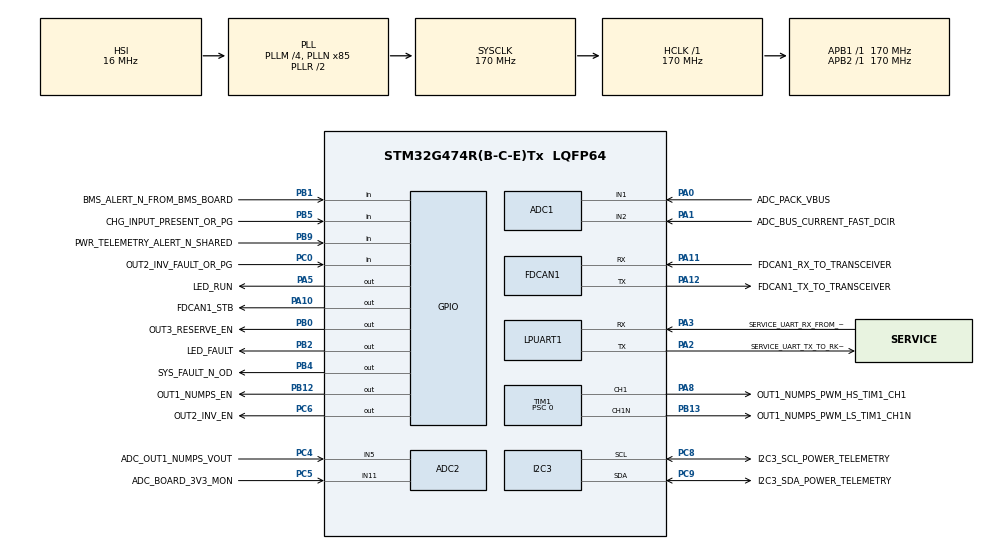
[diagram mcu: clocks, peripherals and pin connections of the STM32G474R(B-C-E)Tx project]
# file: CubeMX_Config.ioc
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ADC1.Channel-0\#ChannelRegularConversion=ADC_CHANNEL_1
ADC1.Channel-1\#ChannelRegularConversion=ADC_CHANNEL_2
ADC1.NbrOfConversionFlag=2
ADC1.OffsetNumber-0\#ChannelRegularConversion=ADC_OFFSET_NONE
ADC1.OffsetNumber-1\#ChannelRegularConversion=ADC_OFFSET_NONE
ADC1.Rank-0\#ChannelRegularConversion=1
ADC1.Rank-1\#ChannelRegularConversion=2
ADC1.SamplingTime-0\#ChannelRegularConversion=ADC_SAMPLETIME_47CYCLES_5
ADC1.SamplingTime-1\#ChannelRegularConversion=ADC_SAMPLETIME_47CYCLES_5
ADC1.master=1
ADC2.Channel-0\#ChannelRegularConversion=ADC_CHANNEL_5
ADC2.Channel-1\#ChannelRegularConversion=ADC_CHANNEL_11
ADC2.NbrOfConversionFlag=2
ADC2.OffsetNumber-0\#ChannelRegularConversion=ADC_OFFSET_NONE
ADC2.OffsetNumber-1\#ChannelRegularConversion=ADC_OFFSET_NONE
ADC2.Rank-0\#ChannelRegularConversion=1
ADC2.Rank-1\#ChannelRegularConversion=2
ADC2.SamplingTime-0\#ChannelRegularConversion=ADC_SAMPLETIME_47CYCLES_5
ADC2.SamplingTime-1\#ChannelRegularConversion=ADC_SAMPLETIME_47CYCLES_5
FDCAN1.AutoRetransmission=ENABLE
FDCAN1.CalculateBaudRateNominal=500000
FDCAN1.CalculateTimeBitNominal=2000
FDCAN1.CalculateTimeQuantumNominal=100.0
FDCAN1.ExtFiltersNbr=1
FDCAN1.FrameFormat=FDCAN_FRAME_CLASSIC
FDCAN1.Mode=FDCAN_MODE_NORMAL
FDCAN1.NominalPrescaler=17
FDCAN1.NominalSyncJumpWidth=3
FDCAN1.NominalTimeSeg1=16
FDCAN1.NominalTimeSeg2=3
FDCAN1.StdFiltersNbr=1
I2C3.Timing=0x40B285C2
Mcu.Family=STM32G4
Mcu.Name=STM32G474R(B-C-E)Tx
Mcu.Package=LQFP64
NVIC.PriorityGroup=NVIC_PRIORITYGROUP_4
PA0.GPIO_Label=ADC_PACK_VBUS
PA0.Mode=IN1-Single-Ended
PA0.Signal=ADC1_IN1
PA1.GPIO_Label=ADC_BUS_CURRENT_FAST_DCIR
PA1.Mode=IN2-Single-Ended
PA1.Signal=ADC1_IN2
PA10.GPIO_Label=FDCAN1_STB
PA10.GPIO_ModeDefaultOutputPP=GPIO_MODE_OUTPUT_PP
PA10.GPIO_PuPd=GPIO_PULLDOWN
PA10.PinState=GPIO_PIN_RESET
PA10.Signal=GPIO_Output
PA11.GPIO_Label=FDCAN1_RX_TO_TRANSCEIVER
PA11.Mode=FDCAN_Activate
PA11.Signal=FDCAN1_RX
PA12.GPIO_Label=FDCAN1_TX_TO_TRANSCEIVER
PA12.Mode=FDCAN_Activate
PA12.Signal=FDCAN1_TX
PA13.Mode=Serial_Wire
PA13.Signal=SYS_JTMS-SWDIO
PA14.Mode=Serial_Wire
PA14.Signal=SYS_JTCK-SWCLK
PA2.Mode=Asynchronous
PA2.GPIO_Label=SERVICE_UART_TX_TO_RK3506_OR_USBTTL
PA2.Signal=LPUART1_TX
PA3.Mode=Asynchronous
PA3.GPIO_Label=SERVICE_UART_RX_FROM_RK3506_OR_USBTTL
PA3.Signal=LPUART1_RX
PA5.GPIO_Label=LED_RUN
PA5.GPIO_ModeDefaultOutputPP=GPIO_MODE_OUTPUT_PP
PA5.PinState=GPIO_PIN_RESET
PA5.Signal=GPIO_Output
PA8.GPIO_Label=OUT1_NUMPS_PWM_HS_TIM1_CH1
PA8.Signal=S_TIM1_CH1
PB4.GPIO_Label=SYS_FAULT_N_OD
PB4.GPIO_ModeDefaultOutputPP=GPIO_MODE_OUTPUT_OD
PB4.GPIO_PuPd=GPIO_NOPULL
PB4.PinState=GPIO_PIN_SET
PB4.Signal=GPIO_Output
PB0.GPIO_Label=OUT3_RESERVE_EN
PB0.GPIO_ModeDefaultOutputPP=GPIO_MODE_OUTPUT_PP
PB0.PinState=GPIO_PIN_RESET
PB0.Signal=GPIO_Output
PB1.GPIO_Label=BMS_ALERT_N_FROM_BMS_BOARD
PB1.GPIO_PuPd=GPIO_PULLUP
PB1.Signal=GPIO_Input
PB12.GPIO_Label=OUT1_NUMPS_EN
PB12.GPIO_ModeDefaultOutputPP=GPIO_MODE_OUTPUT_PP
PB12.GPIO_PuPd=GPIO_PULLDOWN
PB12.PinState=GPIO_PIN_RESET
PB12.Signal=GPIO_Output
PB13.GPIO_Label=OUT1_NUMPS_PWM_LS_TIM1_CH1N
PB13.Mode=PWM Generation1 CH1N
PB13.Signal=TIM1_CH1N
PB2.GPIO_Label=LED_FAULT
PB2.GPIO_ModeDefaultOutputPP=GPIO_MODE_OUTPUT_PP
PB2.PinState=GPIO_PIN_RESET
PB2.Signal=GPIO_Output
PB5.GPIO_Label=CHG_INPUT_PRESENT_OR_PG
PB5.GPIO_PuPd=GPIO_PULLDOWN
PB5.Signal=GPIO_Input
PB9.GPIO_Label=PWR_TELEMETRY_ALERT_N_SHARED
PB9.GPIO_PuPd=GPIO_PULLUP
PB9.Signal=GPIO_Input
PC0.GPIO_Label=OUT2_INV_FAULT_OR_PG
PC0.GPIO_PuPd=GPIO_PULLUP
PC0.Signal=GPIO_Input
PC14-OSC32_IN.Mode=LSE-External-Oscillator
PC14-OSC32_IN.Signal=RCC_OSC32_IN
PC15-OSC32_OUT.Mode=LSE-External-Oscillator
PC15-OSC32_OUT.Signal=RCC_OSC32_OUT
PC4.GPIO_Label=ADC_OUT1_NUMPS_VOUT
PC4.Mode=IN5-Single-Ended
PC4.Signal=ADC2_IN5
PC5.GPIO_Label=ADC_BOARD_3V3_MON
PC5.Mode=IN11-Single-Ended
PC5.Signal=ADC2_IN11
PC6.GPIO_Label=OUT2_INV_EN
PC6.GPIO_ModeDefaultOutputPP=GPIO_MODE_OUTPUT_PP
PC6.GPIO_PuPd=GPIO_PULLDOWN
PC6.PinState=GPIO_PIN_RESET
PC6.Signal=GPIO_Output
PC8.Mode=I2C
PC8.GPIO_Label=I2C3_SCL_POWER_TELEMETRY
PC8.Signal=I2C3_SCL
PC9.Mode=I2C
PC9.GPIO_Label=I2C3_SDA_POWER_TELEMETRY
PC9.Signal=I2C3_SDA
PF0-OSC_IN.Mode=HSE-External-Oscillator
PF0-OSC_IN.Signal=RCC_OSC_IN
PF1-OSC_OUT.Mode=HSE-External-Oscillator
PF1-OSC_OUT.Signal=RCC_OSC_OUT
ProjectManager.HeapSize=0x200
ProjectManager.StackSize=0x400
ProjectManager.TargetToolchain=MDK-ARM V5
RCC.ADC12Freq_Value=170000000
RCC.ADC345Freq_Value=170000000
RCC.AHBFreq_Value=170000000
RCC.APB1Freq_Value=170000000
RCC.APB1TimFreq_Value=170000000
RCC.APB2Freq_Value=170000000
RCC.APB2TimFreq_Value=170000000
RCC.CortexFreq_Value=170000000
RCC.EXTERNAL_CLOCK_VALUE=12288000
RCC.HCLKFreq_Value=170000000
RCC.HSE_VALUE=24000000
RCC.HSI48_VALUE=48000000
RCC.HSI_VALUE=16000000
RCC.PLLM=RCC_PLLM_DIV4
RCC.PLLN=85
RCC.RTCClockSelection=RCC_RTCCLKSOURCE_LSE
RCC.SYSCLKFreq_VALUE=170000000
RCC.SYSCLKSource=RCC_SYSCLKSOURCE_PLLCLK
RCC.USBFreq_Value=170000000
RCC.VCOOutputFreq_Value=340000000
SH.S_TIM1_CH1.0=TIM1_CH1,PWM Generation1 CH1
TIM1.Channel-PWM\ Generation1\ CH1=TIM_CHANNEL_1
TIM1.Channel-PWM\ Generation1\ CH1N=TIM_CHANNEL_1
TIM1.Period=4358
TIM1.Prescaler=0
TIM1.Pulse-PWM\ Generation1\ CH1=0
VP_SYS_VS_DBSignals.Mode=DisableDeadBatterySignals
VP_TIM1_VS_ClockSourceINT.Mode=Internal
board=NUCLEO-G474RE

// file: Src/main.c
/* USER CODE BEGIN Header */
/**
  ******************************************************************************
  * @file           : main.c
  * @brief          : Main program body
  ******************************************************************************
  * @attention
  *
  * Copyright (c) 2026 STMicroelectronics.
  * All rights reserved.
  *
  * This software is licensed under terms that can be found in the LICENSE file
  * in the root directory of this software component.
  * If no LICENSE file comes with this software, it is provided AS-IS.
  *
  ******************************************************************************
  */
/* USER CODE END Header */
#include "main.h"

ADC_HandleTypeDef hadc1;
ADC_HandleTypeDef hadc2;

FDCAN_HandleTypeDef hfdcan1;

I2C_HandleTypeDef hi2c3;

UART_HandleTypeDef hlpuart1;

TIM_HandleTypeDef htim1;

void SystemClock_Config(void);
static void MX_GPIO_Init(void);
static void MX_ADC1_Init(void);
static void MX_ADC2_Init(void);
static void MX_TIM1_Init(void);
static void MX_FDCAN1_Init(void);
static void MX_I2C3_Init(void);
static void MX_LPUART1_UART_Init(void);

int main(void)
{

  /* MCU Configuration--------------------------------------------------------*/

  /* Reset of all peripherals, Initializes the Flash interface and the Systick. */
  HAL_Init();

  /* Configure the system clock */
  SystemClock_Config();

  /* Initialize all configured peripherals */
  MX_GPIO_Init();
  MX_ADC1_Init();
  MX_ADC2_Init();
  MX_TIM1_Init();
  MX_FDCAN1_Init();
  MX_I2C3_Init();
  MX_LPUART1_UART_Init();

  /* Infinite loop */
  while (1)
  {

  }
}

void SystemClock_Config(void)
{
  RCC_OscInitTypeDef RCC_OscInitStruct = {0};
  RCC_ClkInitTypeDef RCC_ClkInitStruct = {0};

  /** Configure the main internal regulator output voltage
  */
  HAL_PWREx_ControlVoltageScaling(PWR_REGULATOR_VOLTAGE_SCALE1_BOOST);

  /** Initializes the RCC Oscillators according to the specified parameters
  * in the RCC_OscInitTypeDef structure.
  */
  RCC_OscInitStruct.OscillatorType = RCC_OSCILLATORTYPE_HSI;
  RCC_OscInitStruct.HSIState = RCC_HSI_ON;
  RCC_OscInitStruct.HSICalibrationValue = RCC_HSICALIBRATION_DEFAULT;
  RCC_OscInitStruct.PLL.PLLState = RCC_PLL_ON;
  RCC_OscInitStruct.PLL.PLLSource = RCC_PLLSOURCE_HSI;
  RCC_OscInitStruct.PLL.PLLM = RCC_PLLM_DIV4;
  RCC_OscInitStruct.PLL.PLLN = 85;
  RCC_OscInitStruct.PLL.PLLP = RCC_PLLP_DIV2;
  RCC_OscInitStruct.PLL.PLLQ = RCC_PLLQ_DIV2;
  RCC_OscInitStruct.PLL.PLLR = RCC_PLLR_DIV2;
  if (HAL_RCC_OscConfig(&RCC_OscInitStruct) != HAL_OK)
  {
    Error_Handler();
  }

  /** Initializes the CPU, AHB and APB buses clocks
  */
  RCC_ClkInitStruct.ClockType = RCC_CLOCKTYPE_HCLK|RCC_CLOCKTYPE_SYSCLK
                              |RCC_CLOCKTYPE_PCLK1|RCC_CLOCKTYPE_PCLK2;
  RCC_ClkInitStruct.SYSCLKSource = RCC_SYSCLKSOURCE_PLLCLK;
  RCC_ClkInitStruct.AHBCLKDivider = RCC_SYSCLK_DIV1;
  RCC_ClkInitStruct.APB1CLKDivider = RCC_HCLK_DIV1;
  RCC_ClkInitStruct.APB2CLKDivider = RCC_HCLK_DIV1;

  if (HAL_RCC_ClockConfig(&RCC_ClkInitStruct, FLASH_LATENCY_4) != HAL_OK)
  {
    Error_Handler();
  }
}

static void MX_ADC1_Init(void)
{

  ADC_MultiModeTypeDef multimode = {0};
  ADC_ChannelConfTypeDef sConfig = {0};

  /** Common config
  */
  hadc1.Instance = ADC1;
  hadc1.Init.ClockPrescaler = ADC_CLOCK_SYNC_PCLK_DIV4;
  hadc1.Init.Resolution = ADC_RESOLUTION_12B;
  hadc1.Init.DataAlign = ADC_DATAALIGN_RIGHT;
  hadc1.Init.GainCompensation = 0;
  hadc1.Init.ScanConvMode = ADC_SCAN_DISABLE;
  hadc1.Init.EOCSelection = ADC_EOC_SINGLE_CONV;
  hadc1.Init.LowPowerAutoWait = DISABLE;
  hadc1.Init.ContinuousConvMode = DISABLE;
  hadc1.Init.NbrOfConversion = 1;
  hadc1.Init.DiscontinuousConvMode = DISABLE;
  hadc1.Init.ExternalTrigConv = ADC_SOFTWARE_START;
  hadc1.Init.ExternalTrigConvEdge = ADC_EXTERNALTRIGCONVEDGE_NONE;
  hadc1.Init.DMAContinuousRequests = DISABLE;
  hadc1.Init.Overrun = ADC_OVR_DATA_PRESERVED;
  hadc1.Init.OversamplingMode = DISABLE;
  if (HAL_ADC_Init(&hadc1) != HAL_OK)
  {
    Error_Handler();
  }

  /** Configure the ADC multi-mode
  */
  multimode.Mode = ADC_MODE_INDEPENDENT;
  if (HAL_ADCEx_MultiModeConfigChannel(&hadc1, &multimode) != HAL_OK)
  {
    Error_Handler();
  }

  /** Configure Regular Channel
  */
  sConfig.Channel = ADC_CHANNEL_1;
  sConfig.Rank = ADC_REGULAR_RANK_1;
  sConfig.SamplingTime = ADC_SAMPLETIME_2CYCLES_5;
  sConfig.SingleDiff = ADC_SINGLE_ENDED;
  sConfig.OffsetNumber = ADC_OFFSET_NONE;
  sConfig.Offset = 0;
  if (HAL_ADC_ConfigChannel(&hadc1, &sConfig) != HAL_OK)
  {
    Error_Handler();
  }

}

static void MX_ADC2_Init(void)
{

  ADC_ChannelConfTypeDef sConfig = {0};

  /** Common config
  */
  hadc2.Instance = ADC2;
  hadc2.Init.ClockPrescaler = ADC_CLOCK_SYNC_PCLK_DIV4;
  hadc2.Init.Resolution = ADC_RESOLUTION_12B;
  hadc2.Init.DataAlign = ADC_DATAALIGN_RIGHT;
  hadc2.Init.GainCompensation = 0;
  hadc2.Init.ScanConvMode = ADC_SCAN_DISABLE;
  hadc2.Init.EOCSelection = ADC_EOC_SINGLE_CONV;
  hadc2.Init.LowPowerAutoWait = DISABLE;
  hadc2.Init.ContinuousConvMode = DISABLE;
  hadc2.Init.NbrOfConversion = 1;
  hadc2.Init.DiscontinuousConvMode = DISABLE;
  hadc2.Init.ExternalTrigConv = ADC_SOFTWARE_START;
  hadc2.Init.ExternalTrigConvEdge = ADC_EXTERNALTRIGCONVEDGE_NONE;
  hadc2.Init.DMAContinuousRequests = DISABLE;
  hadc2.Init.Overrun = ADC_OVR_DATA_PRESERVED;
  hadc2.Init.OversamplingMode = DISABLE;
  if (HAL_ADC_Init(&hadc2) != HAL_OK)
  {
    Error_Handler();
  }

  /** Configure Regular Channel
  */
  sConfig.Channel = ADC_CHANNEL_5;
  sConfig.Rank = ADC_REGULAR_RANK_1;
  sConfig.SamplingTime = ADC_SAMPLETIME_2CYCLES_5;
  sConfig.SingleDiff = ADC_SINGLE_ENDED;
  sConfig.OffsetNumber = ADC_OFFSET_NONE;
  sConfig.Offset = 0;
  if (HAL_ADC_ConfigChannel(&hadc2, &sConfig) != HAL_OK)
  {
    Error_Handler();
  }

}

static void MX_FDCAN1_Init(void)
{

  hfdcan1.Instance = FDCAN1;
  hfdcan1.Init.ClockDivider = FDCAN_CLOCK_DIV1;
  hfdcan1.Init.FrameFormat = FDCAN_FRAME_CLASSIC;
  hfdcan1.Init.Mode = FDCAN_MODE_NORMAL;
  hfdcan1.Init.AutoRetransmission = ENABLE;
  hfdcan1.Init.TransmitPause = DISABLE;
  hfdcan1.Init.ProtocolException = DISABLE;
  hfdcan1.Init.NominalPrescaler = 17;
  hfdcan1.Init.NominalSyncJumpWidth = 3;
  hfdcan1.Init.NominalTimeSeg1 = 16;
  hfdcan1.Init.NominalTimeSeg2 = 3;
  hfdcan1.Init.DataPrescaler = 1;
  hfdcan1.Init.DataSyncJumpWidth = 1;
  hfdcan1.Init.DataTimeSeg1 = 1;
  hfdcan1.Init.DataTimeSeg2 = 1;
  hfdcan1.Init.StdFiltersNbr = 1;
  hfdcan1.Init.ExtFiltersNbr = 1;
  hfdcan1.Init.TxFifoQueueMode = FDCAN_TX_FIFO_OPERATION;
  if (HAL_FDCAN_Init(&hfdcan1) != HAL_OK)
  {
    Error_Handler();
  }

}

static void MX_I2C3_Init(void)
{

  hi2c3.Instance = I2C3;
  hi2c3.Init.Timing = 0x40B285C2;
  hi2c3.Init.OwnAddress1 = 0;
  hi2c3.Init.AddressingMode = I2C_ADDRESSINGMODE_7BIT;
  hi2c3.Init.DualAddressMode = I2C_DUALADDRESS_DISABLE;
  hi2c3.Init.OwnAddress2 = 0;
  hi2c3.Init.OwnAddress2Masks = I2C_OA2_NOMASK;
  hi2c3.Init.GeneralCallMode = I2C_GENERALCALL_DISABLE;
  hi2c3.Init.NoStretchMode = I2C_NOSTRETCH_DISABLE;
  if (HAL_I2C_Init(&hi2c3) != HAL_OK)
  {
    Error_Handler();
  }

  /** Configure Analogue filter
  */
  if (HAL_I2CEx_ConfigAnalogFilter(&hi2c3, I2C_ANALOGFILTER_ENABLE) != HAL_OK)
  {
    Error_Handler();
  }

  /** Configure Digital filter
  */
  if (HAL_I2CEx_ConfigDigitalFilter(&hi2c3, 0) != HAL_OK)
  {
    Error_Handler();
  }

}

static void MX_LPUART1_UART_Init(void)
{

  hlpuart1.Instance = LPUART1;
  hlpuart1.Init.BaudRate = 209700;
  hlpuart1.Init.WordLength = UART_WORDLENGTH_8B;
  hlpuart1.Init.StopBits = UART_STOPBITS_1;
  hlpuart1.Init.Parity = UART_PARITY_NONE;
  hlpuart1.Init.Mode = UART_MODE_TX_RX;
  hlpuart1.Init.HwFlowCtl = UART_HWCONTROL_NONE;
  hlpuart1.Init.OneBitSampling = UART_ONE_BIT_SAMPLE_DISABLE;
  hlpuart1.Init.ClockPrescaler = UART_PRESCALER_DIV1;
  hlpuart1.AdvancedInit.AdvFeatureInit = UART_ADVFEATURE_NO_INIT;
  if (HAL_UART_Init(&hlpuart1) != HAL_OK)
  {
    Error_Handler();
  }
  if (HAL_UARTEx_SetTxFifoThreshold(&hlpuart1, UART_TXFIFO_THRESHOLD_1_8) != HAL_OK)
  {
    Error_Handler();
  }
  if (HAL_UARTEx_SetRxFifoThreshold(&hlpuart1, UART_RXFIFO_THRESHOLD_1_8) != HAL_OK)
  {
    Error_Handler();
  }
  if (HAL_UARTEx_DisableFifoMode(&hlpuart1) != HAL_OK)
  {
    Error_Handler();
  }

}

static void MX_TIM1_Init(void)
{

  TIM_ClockConfigTypeDef sClockSourceConfig = {0};
  TIM_MasterConfigTypeDef sMasterConfig = {0};
  TIM_OC_InitTypeDef sConfigOC = {0};
  TIM_BreakDeadTimeConfigTypeDef sBreakDeadTimeConfig = {0};

  htim1.Instance = TIM1;
  htim1.Init.Prescaler = 0;
  htim1.Init.CounterMode = TIM_COUNTERMODE_UP;
  htim1.Init.Period = 4358;
  htim1.Init.ClockDivision = TIM_CLOCKDIVISION_DIV1;
  htim1.Init.RepetitionCounter = 0;
  htim1.Init.AutoReloadPreload = TIM_AUTORELOAD_PRELOAD_DISABLE;
  if (HAL_TIM_Base_Init(&htim1) != HAL_OK)
  {
    Error_Handler();
  }
  sClockSourceConfig.ClockSource = TIM_CLOCKSOURCE_INTERNAL;
  if (HAL_TIM_ConfigClockSource(&htim1, &sClockSourceConfig) != HAL_OK)
  {
    Error_Handler();
  }
  if (HAL_TIM_PWM_Init(&htim1) != HAL_OK)
  {
    Error_Handler();
  }
  sMasterConfig.MasterOutputTrigger = TIM_TRGO_RESET;
  sMasterConfig.MasterOutputTrigger2 = TIM_TRGO2_RESET;
  sMasterConfig.MasterSlaveMode = TIM_MASTERSLAVEMODE_DISABLE;
  if (HAL_TIMEx_MasterConfigSynchronization(&htim1, &sMasterConfig) != HAL_OK)
  {
    Error_Handler();
  }
  sConfigOC.OCMode = TIM_OCMODE_PWM1;
  sConfigOC.Pulse = 0;
  sConfigOC.OCPolarity = TIM_OCPOLARITY_HIGH;
  sConfigOC.OCNPolarity = TIM_OCNPOLARITY_HIGH;
  sConfigOC.OCFastMode = TIM_OCFAST_DISABLE;
  sConfigOC.OCIdleState = TIM_OCIDLESTATE_RESET;
  sConfigOC.OCNIdleState = TIM_OCNIDLESTATE_RESET;
  if (HAL_TIM_PWM_ConfigChannel(&htim1, &sConfigOC, TIM_CHANNEL_1) != HAL_OK)
  {
    Error_Handler();
  }
  sBreakDeadTimeConfig.OffStateRunMode = TIM_OSSR_DISABLE;
  sBreakDeadTimeConfig.OffStateIDLEMode = TIM_OSSI_DISABLE;
  sBreakDeadTimeConfig.LockLevel = TIM_LOCKLEVEL_OFF;
  sBreakDeadTimeConfig.DeadTime = 0;
  sBreakDeadTimeConfig.BreakState = TIM_BREAK_DISABLE;
  sBreakDeadTimeConfig.BreakPolarity = TIM_BREAKPOLARITY_HIGH;
  sBreakDeadTimeConfig.BreakFilter = 0;
  sBreakDeadTimeConfig.BreakAFMode = TIM_BREAK_AFMODE_INPUT;
  sBreakDeadTimeConfig.Break2State = TIM_BREAK2_DISABLE;
  sBreakDeadTimeConfig.Break2Polarity = TIM_BREAK2POLARITY_HIGH;
  sBreakDeadTimeConfig.Break2Filter = 0;
  sBreakDeadTimeConfig.Break2AFMode = TIM_BREAK_AFMODE_INPUT;
  sBreakDeadTimeConfig.AutomaticOutput = TIM_AUTOMATICOUTPUT_DISABLE;
  if (HAL_TIMEx_ConfigBreakDeadTime(&htim1, &sBreakDeadTimeConfig) != HAL_OK)
  {
    Error_Handler();
  }
  HAL_TIM_MspPostInit(&htim1);

}

static void MX_GPIO_Init(void)
{
  GPIO_InitTypeDef GPIO_InitStruct = {0};

  /* GPIO Ports Clock Enable */
  __HAL_RCC_GPIOC_CLK_ENABLE();
  __HAL_RCC_GPIOF_CLK_ENABLE();
  __HAL_RCC_GPIOA_CLK_ENABLE();
  __HAL_RCC_GPIOB_CLK_ENABLE();

  /*Configure GPIO pin Output Level */
  HAL_GPIO_WritePin(NUCLEO_LD2_TEST_NEW_GPIO_Port, NUCLEO_LD2_TEST_NEW_Pin, GPIO_PIN_RESET);

  /*Configure GPIO pin Output Level */
  HAL_GPIO_WritePin(FAULT_N_OD_NEW_FROM_PCB03_HARDWIRE_GPIO_Port, FAULT_N_OD_NEW_FROM_PCB03_HARDWIRE_Pin, GPIO_PIN_SET);

  /*Configure GPIO pin Output Level */
  HAL_GPIO_WritePin(GPIOB, FAN_EN_FROM_ESP32_GPIO16_FAN_Pin|LED_RUN_FROM_ESP32_GPIO2_LED_Pin|LED_FAULT_NEW_Pin|DRV_EN_FROM_ESP32_GPIO32_BUCK_EN_Pin, GPIO_PIN_RESET);

  /*Configure GPIO pin Output Level */
  HAL_GPIO_WritePin(BACKFLOW_EN_FROM_ESP32_GPIO27_BACKFLOW_MOSFET_GPIO_Port, BACKFLOW_EN_FROM_ESP32_GPIO27_BACKFLOW_MOSFET_Pin, GPIO_PIN_RESET);

  /*Configure GPIO pin Output Level */
  HAL_GPIO_WritePin(CAN_STB_GPIO_Port, CAN_STB_Pin, GPIO_PIN_RESET);

  /*Configure GPIO pin : INA226_PV_ALERT_FROM_ESP32_GPIO35_Pin */
  GPIO_InitStruct.Pin = INA226_PV_ALERT_FROM_ESP32_GPIO35_Pin;
  GPIO_InitStruct.Mode = GPIO_MODE_INPUT;
  GPIO_InitStruct.Pull = GPIO_PULLUP;
  HAL_GPIO_Init(INA226_PV_ALERT_FROM_ESP32_GPIO35_GPIO_Port, &GPIO_InitStruct);

  /*Configure GPIO pin : NUCLEO_LD2_TEST_NEW_Pin */
  GPIO_InitStruct.Pin = NUCLEO_LD2_TEST_NEW_Pin;
  GPIO_InitStruct.Mode = GPIO_MODE_OUTPUT_PP;
  GPIO_InitStruct.Pull = GPIO_NOPULL;
  GPIO_InitStruct.Speed = GPIO_SPEED_FREQ_LOW;
  HAL_GPIO_Init(NUCLEO_LD2_TEST_NEW_GPIO_Port, &GPIO_InitStruct);

  /*Configure GPIO pins : FAN_EN_FROM_ESP32_GPIO16_FAN_Pin LED_RUN_FROM_ESP32_GPIO2_LED_Pin LED_FAULT_NEW_Pin */
  GPIO_InitStruct.Pin = FAN_EN_FROM_ESP32_GPIO16_FAN_Pin|LED_RUN_FROM_ESP32_GPIO2_LED_Pin|LED_FAULT_NEW_Pin;
  GPIO_InitStruct.Mode = GPIO_MODE_OUTPUT_PP;
  GPIO_InitStruct.Pull = GPIO_NOPULL;
  GPIO_InitStruct.Speed = GPIO_SPEED_FREQ_LOW;
  HAL_GPIO_Init(GPIOB, &GPIO_InitStruct);

  /*Configure GPIO pin : DRV_EN_FROM_ESP32_GPIO32_BUCK_EN_Pin */
  GPIO_InitStruct.Pin = DRV_EN_FROM_ESP32_GPIO32_BUCK_EN_Pin;
  GPIO_InitStruct.Mode = GPIO_MODE_OUTPUT_PP;
  GPIO_InitStruct.Pull = GPIO_PULLDOWN;
  GPIO_InitStruct.Speed = GPIO_SPEED_FREQ_LOW;
  HAL_GPIO_Init(DRV_EN_FROM_ESP32_GPIO32_BUCK_EN_GPIO_Port, &GPIO_InitStruct);

  /*Configure GPIO pin : BACKFLOW_EN_FROM_ESP32_GPIO27_BACKFLOW_MOSFET_Pin */
  GPIO_InitStruct.Pin = BACKFLOW_EN_FROM_ESP32_GPIO27_BACKFLOW_MOSFET_Pin;
  GPIO_InitStruct.Mode = GPIO_MODE_OUTPUT_PP;
  GPIO_InitStruct.Pull = GPIO_PULLDOWN;
  GPIO_InitStruct.Speed = GPIO_SPEED_FREQ_LOW;
  HAL_GPIO_Init(BACKFLOW_EN_FROM_ESP32_GPIO27_BACKFLOW_MOSFET_GPIO_Port, &GPIO_InitStruct);

  /*Configure GPIO pin : CAN_STB_Pin */
  GPIO_InitStruct.Pin = CAN_STB_Pin;
  GPIO_InitStruct.Mode = GPIO_MODE_OUTPUT_PP;
  GPIO_InitStruct.Pull = GPIO_PULLDOWN;
  GPIO_InitStruct.Speed = GPIO_SPEED_FREQ_LOW;
  HAL_GPIO_Init(CAN_STB_GPIO_Port, &GPIO_InitStruct);

  /*Configure GPIO pin : FAULT_N_OD_NEW_FROM_PCB03_HARDWIRE_Pin */
  GPIO_InitStruct.Pin = FAULT_N_OD_NEW_FROM_PCB03_HARDWIRE_Pin;
  GPIO_InitStruct.Mode = GPIO_MODE_OUTPUT_OD;
  GPIO_InitStruct.Pull = GPIO_NOPULL;
  GPIO_InitStruct.Speed = GPIO_SPEED_FREQ_LOW;
  HAL_GPIO_Init(FAULT_N_OD_NEW_FROM_PCB03_HARDWIRE_GPIO_Port, &GPIO_InitStruct);

  /*Configure GPIO pin : CHG_EN_IN_NEW_FROM_PCB03_HARDWIRE_Pin */
  GPIO_InitStruct.Pin = CHG_EN_IN_NEW_FROM_PCB03_HARDWIRE_Pin;
  GPIO_InitStruct.Mode = GPIO_MODE_INPUT;
  GPIO_InitStruct.Pull = GPIO_PULLDOWN;
  HAL_GPIO_Init(CHG_EN_IN_NEW_FROM_PCB03_HARDWIRE_GPIO_Port, &GPIO_InitStruct);

  /*Configure GPIO pin : INA226_OUT_ALERT_FROM_ESP32_GPIO34_Pin */
  GPIO_InitStruct.Pin = INA226_OUT_ALERT_FROM_ESP32_GPIO34_Pin;
  GPIO_InitStruct.Mode = GPIO_MODE_INPUT;
  GPIO_InitStruct.Pull = GPIO_PULLUP;
  HAL_GPIO_Init(INA226_OUT_ALERT_FROM_ESP32_GPIO34_GPIO_Port, &GPIO_InitStruct);

}

void Error_Handler(void)
{
  __disable_irq();
  while (1)
  {
  }
}
